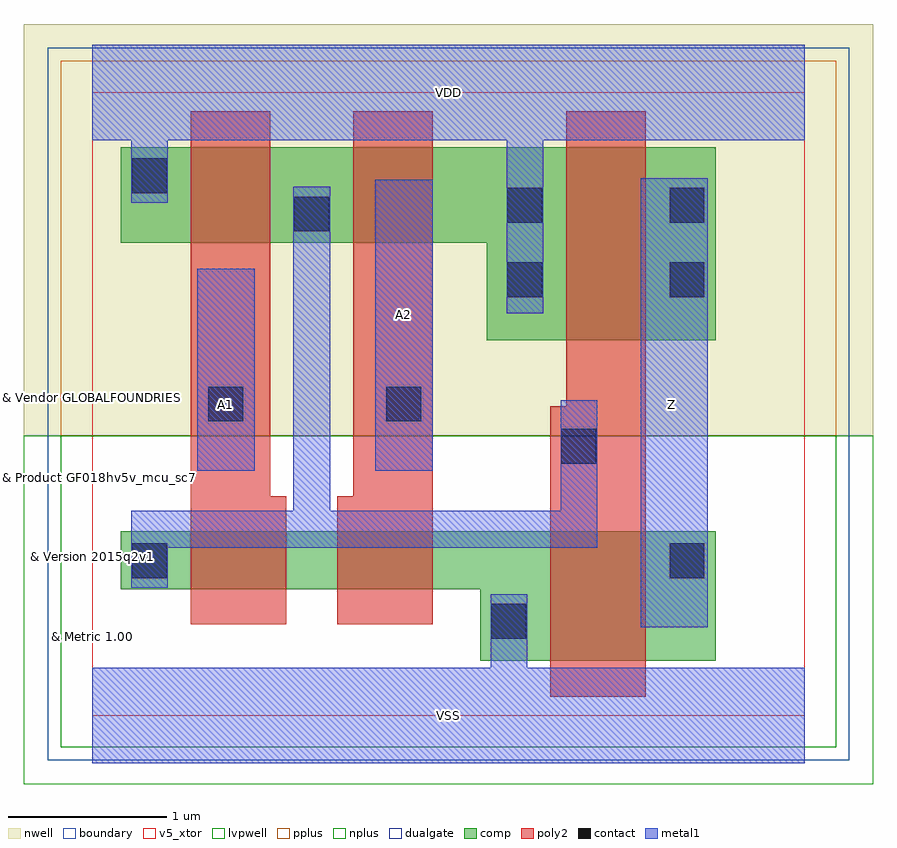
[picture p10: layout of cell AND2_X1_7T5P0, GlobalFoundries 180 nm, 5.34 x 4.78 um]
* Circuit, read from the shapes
.subckt AND2_X1_7T5P0 A1 A2 VDD VSS Z
XM1 n1 A1 n2 VSUBS nfet_05v0 w=0.365u l=0.6u
XM2 VSS A2 n1 VSUBS nfet_05v0 w=0.365u l=0.6u
XM3 Z n2 VSS VSUBS nfet_05v0 w=0.815u l=0.6u
XM4 n2 A1 VDD n3 pfet_05v0 w=0.6u l=0.5u
XM5 VDD A2 n2 n3 pfet_05v0 w=0.6u l=0.5u
XM6 Z n2 VDD n3 pfet_05v0 w=1.215u l=0.5u
.ends

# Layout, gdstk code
import gdstk
lib = gdstk.Library(unit=1e-6, precision=1e-09)
def R(c, l, rs):  # rectangles x0, y0, x1, y1
    for r in rs: c.add(gdstk.rectangle(r[:2], r[2:], *l))
def P(c, l, *ps):  # polygons
    for p in ps: c.add(gdstk.Polygon(p, *l))
boundary = (0, 0)
nwell = (21, 0)
comp = (22, 0)
poly2 = (30, 0)
pplus = (31, 0)
nplus = (32, 0)
contact = (33, 0)
metal1 = (34, 0)
dualgate = (55, 0)
v5_xtor = (112, 1)
lvpwell = (204, 0)

and2_x1_7t5p0 = lib.new_cell('AND2_X1_7T5P0')
R(and2_x1_7t5p0, boundary, [(0,0,4.48,3.92)])
R(and2_x1_7t5p0, nwell, [(-0.43,1.76,4.91,4.35)])
P(and2_x1_7t5p0, comp, [(0.18,0.795),(2.44,0.795),(2.44,0.345),(3.92,0.345),(3.92,1.16),(0.18,1.16)],
  [(0.18,2.975),(2.48,2.975),(2.48,2.36),(3.92,2.36),(3.92,3.575),(0.18,3.575)])
P(and2_x1_7t5p0, poly2, [(0.62,0.575),(1.22,0.575),(1.22,1.38),(1.12,1.38),(1.12,3.8),(0.62,3.8)],
  [(1.54,0.575),(2.14,0.575),(2.14,3.8),(1.64,3.8),(1.64,1.38),(1.54,1.38)],
  [(2.88,0.12),(3.48,0.12),(3.48,3.8),(2.98,3.8),(2.98,1.945),(2.88,1.945)])
R(and2_x1_7t5p0, pplus, [(-0.2,1.76,4.68,4.12)])
R(and2_x1_7t5p0, nplus, [(-0.2,-0.2,4.68,1.76)])
R(and2_x1_7t5p0, contact, [(2.51,0.485,2.73,0.705), (0.25,0.865,0.47,1.085), (3.63,0.865,3.85,1.085), (2.95,1.585,3.17,1.805), (0.73,1.85,0.95,2.07), (1.85,1.85,2.07,2.07), (2.61,2.63,2.83,2.85), (3.63,2.63,3.85,2.85), (1.27,3.045,1.49,3.265), (2.61,3.1,2.83,3.32), (3.63,3.1,3.85,3.32), (0.25,3.285,0.47,3.505)])
R(and2_x1_7t5p0, metal1, [(3.45,0.555,3.87,3.38), (0.66,1.54,1.02,2.81), (1.78,1.54,2.14,3.37)])
P(and2_x1_7t5p0, metal1, [(0.245,0.805),(0.475,0.805),(0.475,1.055),(3.175,1.055),(3.175,1.985),(2.945,1.985),(2.945,1.29),(1.495,1.29),(1.495,3.325),(1.265,3.325),(1.265,1.29),(0.245,1.29)],
  [(0,-0.3),(4.48,-0.3),(4.48,0.3),(2.735,0.3),(2.735,0.765),(2.505,0.765),(2.505,0.3),(0,0.3)],
  [(0,3.62),(0.245,3.62),(0.245,3.225),(0.475,3.225),(0.475,3.62),(2.605,3.62),(2.605,2.53),(2.835,2.53),(2.835,3.62),(4.48,3.62),(4.48,4.22),(0,4.22)])
R(and2_x1_7t5p0, dualgate, [(-0.28,-0.28,4.76,4.2)])
R(and2_x1_7t5p0, v5_xtor, [(0,0,4.48,3.92)])
R(and2_x1_7t5p0, lvpwell, [(-0.43,-0.43,4.91,1.76)])
and2_x1_7t5p0.add(gdstk.Label('VDD', (2.24,3.92), layer=34, texttype=10))
and2_x1_7t5p0.add(gdstk.Label('VSS', (2.24,0), layer=34, texttype=10))
and2_x1_7t5p0.add(gdstk.Label('Z', (3.64,1.96), layer=34, texttype=10))
and2_x1_7t5p0.add(gdstk.Label('A1', (0.84,1.96), layer=34, texttype=10))
and2_x1_7t5p0.add(gdstk.Label('A2', (1.96,2.52), layer=34, texttype=10))
and2_x1_7t5p0.add(gdstk.Label('& Vendor GLOBALFOUNDRIES', (0,2), layer=63, texttype=63))
and2_x1_7t5p0.add(gdstk.Label('& Product GF018hv5v_mcu_sc7', (0,1.5), layer=63, texttype=63))
and2_x1_7t5p0.add(gdstk.Label('& Version 2015q2v1', (0,1), layer=63, texttype=63))
and2_x1_7t5p0.add(gdstk.Label('& Metric 1.00', (0,0.5), layer=63, texttype=63))

lib.write_gds('AND2_X1_7T5P0.gds')
